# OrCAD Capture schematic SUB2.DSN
size A4; note: P5000197

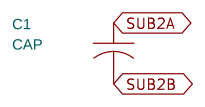
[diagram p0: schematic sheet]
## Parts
C1  CAP  [3456]

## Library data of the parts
C1 = CAP

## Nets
SUB2A: C1.1
SUB2B: C1.2
